VERSION 5.8 ;
BUSBITCHARS "[]" ;
DIVIDERCHAR "/" ;
CLEARANCEMEASURE EUCLIDEAN ;

SITE coresite
    SIZE 0.0450 BY 0.1440 ;
    CLASS CORE ;
    SYMMETRY Y ;
END coresite

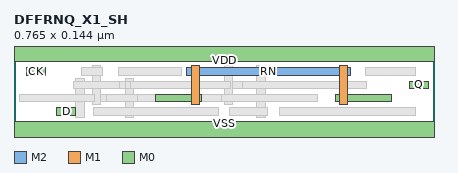
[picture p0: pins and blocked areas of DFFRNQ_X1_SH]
MACRO DFFRNQ_X1_SH
  CLASS CORE ;
  ORIGIN 0 0 ;
  FOREIGN DFFRNQ_X1_SH 0 0 ;
  SIZE 0.7650 BY 0.1440 ;
  SYMMETRY X Y ;
  SITE coresite ;
  PIN RN
    DIRECTION INPUT ;
    USE SIGNAL ;
    PORT
      LAYER M2 ;
        RECT 0.3150 0.1150 0.6120 0.1010 ;
      LAYER M1 ;
        RECT 0.5925 0.1200 0.6075 0.0480 ;
        RECT 0.3225 0.1200 0.3375 0.0480 ;
      LAYER M0 ;
        RECT 0.5850 0.0670 0.6870 0.0530 ;
        RECT 0.2580 0.0670 0.3420 0.0530 ;
    END
  END RN
  PIN CK
    DIRECTION INPUT ;
    USE SIGNAL ;
    PORT
      LAYER M0 ;
        RECT 0.0225 0.1150 0.0570 0.1010 ;
    END
  END CK
  PIN Q
    DIRECTION OUTPUT ;
    USE SIGNAL ;
    PORT
      LAYER M0 ;
        RECT 0.7200 0.0910 0.7545 0.0770 ;
    END
  END Q
  PIN D
    DIRECTION INPUT ;
    USE SIGNAL ;
    PORT
      LAYER M0 ;
        RECT 0.0780 0.0430 0.1125 0.0290 ;
    END
  END D
  PIN VDD
    DIRECTION INOUT ;
    USE POWER ;
    SHAPE ABUTMENT ;
    PORT
      LAYER M0 ;
        RECT 0.0000 0.1260 0.7650 0.1620 ;
    END
  END VDD
  PIN VSS
    DIRECTION INOUT ;
    USE GROUND ;
    SHAPE ABUTMENT ;
    PORT
      LAYER M0 ;
        RECT 0.0000 -0.0180 0.7650 0.0180 ;
    END
  END VSS
  OBS
      LAYER M2 ;
        RECT 0.1350 0.0770 0.4620 0.0910 ;
        RECT 0.1080 0.0530 0.4050 0.0670 ;
      LAYER V0 ;
        RECT 0.5930 0.0530 0.6070 0.0670 ;
        RECT 0.3230 0.0530 0.3370 0.0670 ;
        RECT 0.4430 0.0290 0.4570 0.0430 ;
        RECT 0.4430 0.1010 0.4570 0.1150 ;
        RECT 0.2030 0.0530 0.2170 0.0670 ;
        RECT 0.1430 0.1010 0.1570 0.1150 ;
        RECT 0.3830 0.0530 0.3970 0.0670 ;
        RECT 0.3830 0.1010 0.3970 0.1150 ;
        RECT 0.1130 0.0530 0.1270 0.0670 ;
        RECT 0.1130 0.0770 0.1270 0.0910 ;
      LAYER M1 ;
        RECT 0.4425 0.1200 0.4575 0.0240 ;
        RECT 0.3825 0.1200 0.3975 0.0480 ;
        RECT 0.1425 0.1200 0.1575 0.0480 ;
        RECT 0.2025 0.0960 0.2175 0.0240 ;
        RECT 0.1125 0.0960 0.1275 0.0240 ;
      LAYER V1 ;
        RECT 0.5930 0.1010 0.6070 0.1150 ;
        RECT 0.3230 0.1010 0.3370 0.1150 ;
        RECT 0.4430 0.0770 0.4570 0.0910 ;
        RECT 0.2030 0.0770 0.2170 0.0910 ;
        RECT 0.1430 0.0770 0.1570 0.0910 ;
        RECT 0.3830 0.0530 0.3970 0.0670 ;
        RECT 0.1130 0.0530 0.1270 0.0670 ;
      LAYER M0 ;
        RECT 0.6405 0.1010 0.7320 0.1150 ;
        RECT 0.4380 0.1010 0.5745 0.1150 ;
        RECT 0.3780 0.1010 0.4170 0.1150 ;
        RECT 0.1905 0.1010 0.3045 0.1150 ;
        RECT 0.1230 0.1010 0.1620 0.1150 ;
        RECT 0.4155 0.0770 0.6420 0.0910 ;
        RECT 0.2130 0.0770 0.3945 0.0910 ;
        RECT 0.1080 0.0770 0.1920 0.0910 ;
        RECT 0.3780 0.0530 0.5520 0.0670 ;
        RECT 0.1680 0.0530 0.2250 0.0670 ;
        RECT 0.0105 0.0530 0.1470 0.0670 ;
        RECT 0.4830 0.0290 0.7320 0.0430 ;
        RECT 0.3930 0.0290 0.4620 0.0430 ;
        RECT 0.1455 0.0290 0.3720 0.0430 ;
  END
END DFFRNQ_X1_SH

END LIBRARY
